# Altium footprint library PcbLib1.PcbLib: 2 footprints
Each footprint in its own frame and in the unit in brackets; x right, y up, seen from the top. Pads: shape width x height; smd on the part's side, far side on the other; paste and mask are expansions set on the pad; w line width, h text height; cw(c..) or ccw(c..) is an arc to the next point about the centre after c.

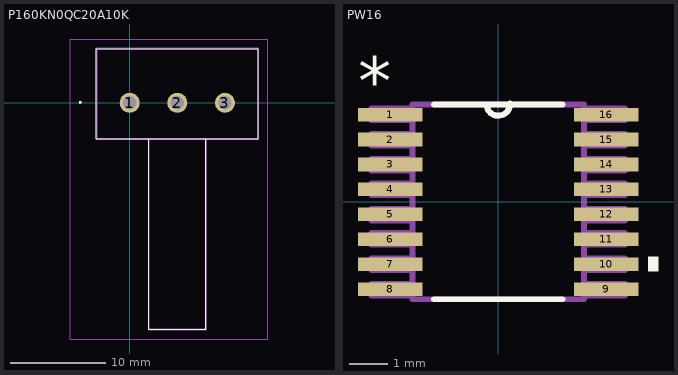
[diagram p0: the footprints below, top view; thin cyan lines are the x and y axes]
## P160KN0QC20A10K [mm]
pads (3):
  round 2.1 hole 1.4: 1(0,0) 2(5,0) 3(10,0)
Top Overlay:
  lines w0.1: -3.5,-3.8 -3.5,5.7 13.5,5.7 13.5,-3.8 -3.5,-3.8 ; 2,-23.8 2,-3.8 8,-3.8 8,-23.8 2,-23.8
  lines w0.2: -5.2,0 ccw(c-5.2,0.05) -5.2,0.1 ; -5.2,0 cw(c-5.2,0.05) -5.2,0.1 ; -5.2,0 ccw(c-5.2,0.05) -5.2,0.1
Mechanical 15:
  lines w0.2: -3.5,-3.8 -3.5,5.7 13.5,5.7 13.5,-3.8 -3.5,-3.8 ; 2,-23.8 2,-3.8 8,-3.8 8,-23.8 2,-23.8
Mechanical 20:
  lines w0.1: -6.25,-24.8 -6.25,6.7 14.5,6.7 14.5,-24.8 -6.25,-24.8

## PW16 [mil]
pads (16):
  rect 66x14 smd: 1(-111,89.57) 2(-111,63.98) 3(-111,38.39) 4(-111,12.8) 5(-111,-12.8) 6(-111,-38.39) 7(-111,-63.98) 8(-111,-89.57) 9(111,-89.57) 10(111,-63.98) 11(111,-38.39) 12(111,-12.8) 13(111,12.8) 14(111,38.39) 15(111,63.98) 16(111,89.57)
Top Overlay:
  region: 164,-71.48 154,-71.48 154,-56.48 164,-56.48
  lines w6: -66,-100 66,-100 ; -66,100 -12,100 66,100 ; -12,100.08 ccw(c0,100.5) 12,100.92
  text "*" at -144,99 h50
Mechanical 13:
  lines w6: -12,100.08 ccw(c0,100.5) 12,100.92 ; -130,-96 -88,-96 -88,-84 -130,-84 -130,-96 ; -130,-70 -88,-70 -88,-58 -130,-58 -130,-70 ; -130,-44 -88,-44 -88,-32 -130,-32 -130,-44 ; -130,-19 -88,-19 -88,-7 -130,-7 -130,-19 ; -130,7 -88,7 -88,19 -130,19 -130,7 ; -130,32 -88,32 -88,44 -130,44 -130,32 ; -130,58 -88,58 -88,70 -130,70 -130,58 ; -130,84 -88,84 -88,96 -130,96 -130,84 ; -88,-100 -88,100 -12,100 88,100 88,-100 -88,-100 ; 88,-96 130,-96 130,-84 88,-84 88,-96 ; 88,-70 130,-70 130,-58 88,-58 88,-70 ; 88,-44 130,-44 130,-32 88,-32 88,-44 ; 88,-19 130,-19 130,-7 88,-7 88,-19 ; 88,7 130,7 130,19 88,19 88,7 ; 88,32 130,32 130,44 88,44 88,32 ; 88,58 130,58 130,70 88,70 88,58 ; 88,84 130,84 130,96 88,96 88,84
  text "*" at -144,99 h50
3D body "step_temp.STEP": height 47.24, standoff 0, extent -125.98,-98.43 125.98,98.43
